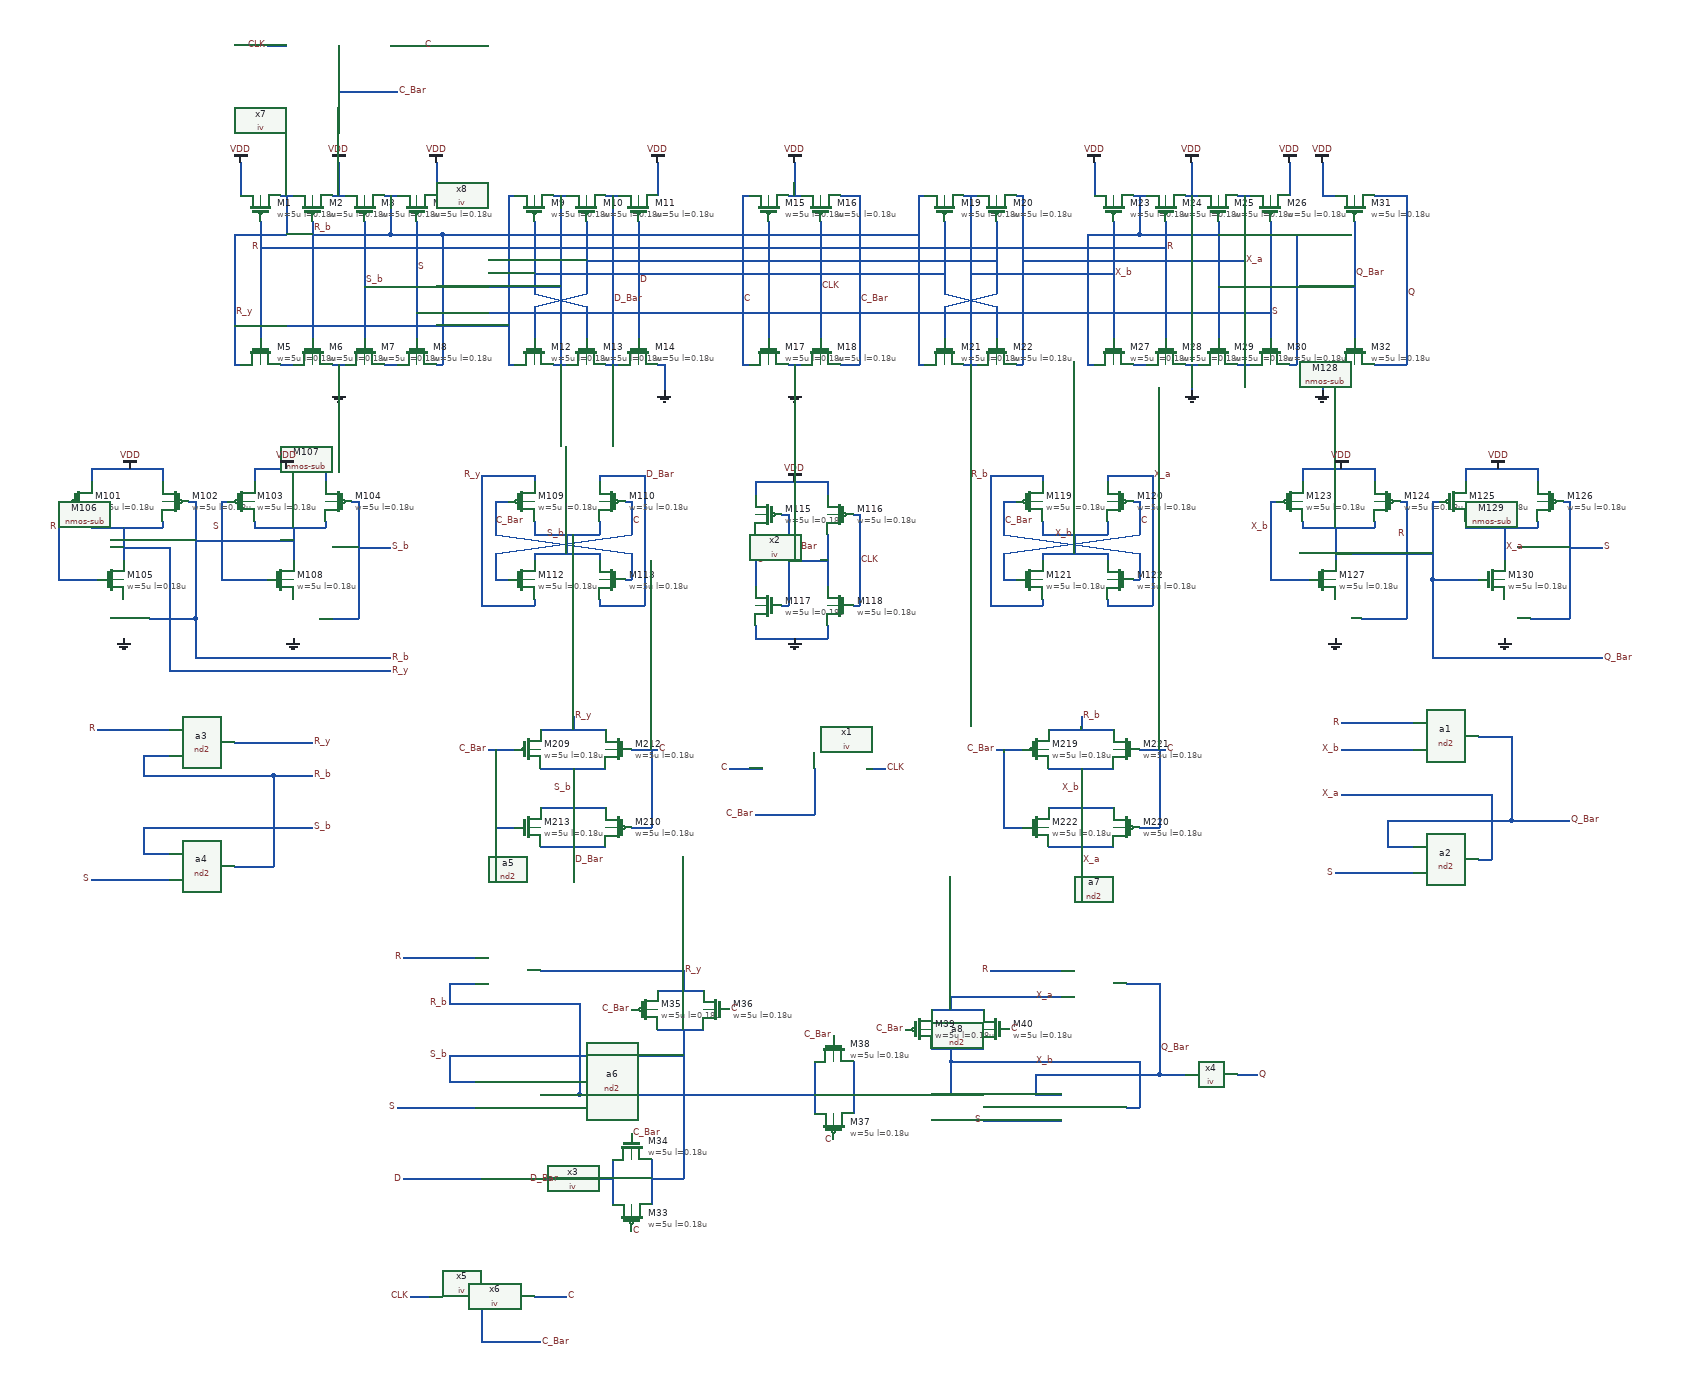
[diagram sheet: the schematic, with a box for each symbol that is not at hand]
v {xschem version=3.4.5 file_version=1.2
}
G {}
K {}
V {}
S {}
E {}
N 480 -1140 480 -1090 {
lab=VDD}
N 540 -1090 560 -1090 {
lab=R_y}
N 620 -1090 640 -1090 {
lab=VDD}
N 700 -1090 720 -1090 {
lab=R_b}
N 780 -1140 780 -1090 {
lab=VDD}
N 630 -1140 630 -1090 {
lab=VDD}
N 550 -1090 550 -1030 {
lab=R_y}
N 480 -1030 550 -1030 {
lab=R_y}
N 470 -1030 480 -1030 {
lab=R_y}
N 470 -830 480 -830 {
lab=R_y}
N 540 -830 560 -830 {
lab=#net1}
N 620 -830 640 -830 {
lab=GND}
N 700 -830 720 -830 {
lab=#net2}
N 780 -830 790 -830 {
lab=R_b}
N 710 -1090 710 -1030 {
lab=R_b}
N 590 -1030 710 -1030 {
lab=R_b}
N 630 -830 630 -790 {
lab=GND}
N 710 -1030 790 -1030 {
lab=R_b}
N 790 -1030 790 -850 {
lab=R_b}
N 890 -1090 900 -1090 {
lab=R_y}
N 890 -1090 890 -850 {
lab=R_y}
N 890 -830 900 -830 {
lab=R_y}
N 470 -890 890 -890 {
lab=R_y}
N 930 -920 1010 -940 {
lab=C}
N 930 -940 1010 -920 {
lab=C_Bar}
N 960 -1090 980 -1090 {
lab=S_b}
N 1040 -1090 1060 -1090 {
lab=D_Bar}
N 970 -1090 970 -850 {
lab=S_b}
N 960 -830 980 -830 {
lab=S_b}
N 1050 -1090 1050 -850 {
lab=D_Bar}
N 1040 -830 1060 -830 {
lab=D_Bar}
N 1090 -1050 1090 -880 {
lab=D}
N 1120 -1140 1120 -1090 {
lab=VDD}
N 1120 -830 1130 -830 {
lab=GND}
N 1130 -830 1130 -790 {
lab=GND}
N 1290 -1050 1290 -890 {
lab=C_Bar}
N 1370 -1050 1370 -890 {
lab=CLK}
N 1320 -1090 1340 -1090 {
lab=VDD}
N 1320 -830 1340 -830 {
lab=GND}
N 1330 -830 1330 -790 {
lab=GND}
N 1250 -1090 1260 -1090 {
lab=C}
N 1250 -1090 1250 -850 {
lab=C}
N 1250 -830 1260 -830 {
lab=C}
N 1330 -1140 1330 -1090 {
lab=VDD}
N 1290 -970 1410 -970 {
lab=C_Bar}
N 1010 -990 1250 -990 {
lab=C}
N 930 -970 1290 -970 {
lab=C_Bar}
N 670 -950 970 -950 {
lab=S_b}
N 1400 -1090 1430 -1090 {
lab=C_Bar}
N 1430 -1090 1430 -850 {
lab=C_Bar}
N 1400 -830 1430 -830 {
lab=C_Bar}
N 1410 -970 1430 -970 {
lab=C_Bar}
N 1520 -1090 1530 -1090 {
lab=R_b}
N 1520 -1090 1520 -850 {
lab=R_b}
N 1520 -830 1530 -830 {
lab=R_b}
N 1560 -920 1640 -940 {
lab=C}
N 1560 -940 1640 -920 {
lab=C_Bar}
N 1590 -1090 1610 -1090 {
lab=#net3}
N 1600 -1090 1600 -850 {
lab=#net3}
N 1590 -830 1610 -830 {
lab=#net3}
N 1680 -1090 1680 -850 {
lab=#net4}
N 1670 -1090 1680 -1090 {
lab=#net4}
N 1670 -830 1680 -830 {
lab=#net4}
N 1430 -970 1560 -970 {
lab=C_Bar}
N 1250 -990 1640 -990 {
lab=C}
N 1790 -1140 1790 -1090 {
lab=VDD}
N 1850 -1090 1870 -1090 {
lab=#net5}
N 1930 -1090 1950 -1090 {
lab=VDD}
N 2010 -1090 2030 -1090 {
lab=#net4}
N 2090 -1140 2090 -1090 {
lab=VDD}
N 1940 -1140 1940 -1090 {
lab=VDD}
N 1780 -830 1790 -830 {
lab=#net5}
N 1820 -1050 1820 -890 {
lab=#net3}
N 1900 -1050 1900 -890 {
lab=R}
N 1980 -1050 1980 -890 {
lab=#net5}
N 2060 -1050 2060 -890 {
lab=S}
N 1850 -830 1870 -830 {
lab=#net6}
N 1930 -830 1950 -830 {
lab=GND}
N 2010 -830 2030 -830 {
lab=#net7}
N 2090 -830 2100 -830 {
lab=#net4}
N 1940 -830 1940 -790 {
lab=GND}
N 1600 -970 1820 -970 {
lab=#net3}
N 930 -1050 930 -940 {
lab=C_Bar}
N 1010 -1050 1010 -940 {
lab=C}
N 930 -920 930 -890 {
lab=C}
N 1010 -920 1010 -890 {
lab=C_Bar}
N 1560 -920 1560 -890 {
lab=C}
N 1640 -920 1640 -890 {
lab=C_Bar}
N 1560 -1050 1560 -940 {
lab=C_Bar}
N 1640 -1050 1640 -940 {
lab=C}
N 750 -910 2060 -910 {
lab=S}
N 2140 -1090 2160 -1090 {
lab=VDD}
N 2140 -1140 2140 -1090 {
lab=VDD}
N 2190 -1050 2190 -890 {
lab=#net5}
N 2140 -830 2160 -830 {
lab=GND}
N 2140 -830 2140 -790 {
lab=GND}
N 510 -1010 1900 -1010 {
lab=R}
N 790 -1030 1520 -1030 {
lab=R_b}
N 790 -850 790 -830 {
lab=R_b}
N 510 -1050 510 -870 {
lab=R}
N 590 -1050 590 -870 {
lab=R_b}
N 670 -1050 670 -870 {
lab=S_b}
N 750 -1050 750 -870 {
lab=S}
N 470 -1030 470 -830 {
lab=R_y}
N 1680 -990 2020 -990 {
lab=#net4}
N 1780 -950 1780 -850 {
lab=#net5}
N 1980 -950 2190 -950 {
lab=#net5}
N 890 -850 890 -830 {
lab=R_y}
N 930 -890 930 -870 {
lab=C}
N 1010 -890 1010 -870 {
lab=C_Bar}
N 1050 -850 1050 -830 {
lab=D_Bar}
N 1090 -880 1090 -870 {
lab=D}
N 1250 -850 1250 -830 {
lab=C}
N 1290 -890 1290 -870 {
lab=C_Bar}
N 1370 -890 1370 -870 {
lab=CLK}
N 1430 -850 1430 -830 {
lab=C_Bar}
N 1520 -850 1520 -830 {
lab=R_b}
N 1560 -890 1560 -870 {
lab=C}
N 1600 -850 1600 -830 {
lab=#net3}
N 1640 -890 1640 -870 {
lab=C_Bar}
N 1680 -850 1680 -830 {
lab=#net4}
N 1780 -850 1780 -830 {
lab=#net5}
N 1820 -890 1820 -870 {
lab=#net3}
N 1900 -890 1900 -870 {
lab=R}
N 1980 -890 1980 -870 {
lab=#net5}
N 2060 -890 2060 -870 {
lab=S}
N 2190 -890 2190 -870 {
lab=#net5}
N 250 -590 250 -580 {
lab=R_y}
N 250 -580 360 -580 {
lab=R_y}
N 360 -590 360 -580 {
lab=R_y}
N 300 -580 300 -530 {
lab=R_y}
N 200 -620 210 -620 {
lab=R}
N 200 -620 200 -500 {
lab=R}
N 200 -500 260 -500 {
lab=R}
N 400 -620 410 -620 {
lab=R_b}
N 410 -620 410 -440 {
lab=R_b}
N 340 -440 410 -440 {
lab=R_b}
N 250 -670 250 -650 {
lab=VDD}
N 250 -670 360 -670 {
lab=VDD}
N 360 -670 360 -650 {
lab=VDD}
N 610 -590 610 -580 {
lab=R_b}
N 500 -580 610 -580 {
lab=R_b}
N 500 -590 500 -580 {
lab=R_b}
N 560 -580 560 -530 {
lab=R_b}
N 650 -620 660 -620 {
lab=S_b}
N 450 -620 460 -620 {
lab=S}
N 610 -670 610 -650 {
lab=VDD}
N 500 -670 610 -670 {
lab=VDD}
N 500 -670 500 -650 {
lab=VDD}
N 410 -560 560 -560 {
lab=R_b}
N 300 -550 370 -550 {
lab=R_y}
N 370 -550 370 -360 {
lab=R_y}
N 450 -500 520 -500 {
lab=S}
N 450 -620 450 -500 {
lab=S}
N 660 -620 660 -440 {
lab=S_b}
N 600 -440 660 -440 {
lab=S_b}
N 1780 -1030 1860 -1030 {
lab=#net5}
N 1780 -1030 1780 -950 {
lab=#net5}
N 2020 -1030 2100 -1030 {
lab=#net4}
N 2100 -1030 2100 -830 {
lab=#net4}
N 1860 -1030 1980 -1030 {
lab=#net5}
N 1860 -1090 1860 -1030 {
lab=#net5}
N 330 -120 330 -80 {
lab=S_b}
N 330 -80 370 -80 {
lab=S_b}
N 330 -230 370 -230 {
lab=R_b}
N 470 -60 530 -60 {
lab=R_b}
N 260 -270 370 -270 {
lab=R}
N 250 -40 370 -40 {
lab=S}
N 330 -120 590 -120 {
lab=S_b}
N 470 -250 590 -250 {
lab=R_y}
N 370 -360 710 -360 {
lab=R_y}
N 660 -550 710 -550 {
lab=S_b}
N 410 -440 410 -380 {
lab=R_b}
N 410 -380 710 -380 {
lab=R_b}
N 530 -200 590 -200 {
lab=R_b}
N 330 -200 530 -200 {
lab=R_b}
N 530 -200 530 -60 {
lab=R_b}
N 330 -230 330 -200 {
lab=R_b}
N 930 -590 930 -570 {
lab=#net8}
N 930 -570 1030 -570 {
lab=#net8}
N 1030 -590 1030 -570 {
lab=#net8}
N 930 -540 930 -530 {
lab=#net8}
N 930 -540 1030 -540 {
lab=#net8}
N 1030 -540 1030 -530 {
lab=#net8}
N 980 -570 980 -540 {
lab=#net8}
N 930 -470 930 -460 {
lab=R_y}
N 1030 -470 1030 -460 {
lab=D_Bar}
N 930 -660 930 -650 {
lab=R_y}
N 1030 -660 1030 -650 {
lab=D_Bar}
N 1070 -620 1080 -620 {
lab=C}
N 1080 -620 1080 -570 {
lab=C}
N 870 -540 1080 -570 {
lab=C}
N 870 -540 870 -500 {
lab=C}
N 870 -500 890 -500 {
lab=C}
N 870 -620 890 -620 {
lab=C_Bar}
N 870 -620 870 -570 {
lab=C_Bar}
N 870 -570 1080 -540 {
lab=C_Bar}
N 1080 -540 1080 -500 {
lab=C_Bar}
N 1070 -500 1080 -500 {
lab=C_Bar}
N 850 -660 930 -660 {
lab=R_y}
N 1030 -660 1100 -660 {
lab=D_Bar}
N 1100 -660 1100 -460 {
lab=D_Bar}
N 1030 -460 1100 -460 {
lab=D_Bar}
N 850 -460 930 -460 {
lab=R_y}
N 850 -660 850 -460 {
lab=R_y}
N 940 -90 1040 -90 {
lab=D_Bar}
N 940 -150 1040 -150 {
lab=S_b}
N 940 -210 1040 -210 {
lab=S_b}
N 940 -270 1040 -270 {
lab=R_y}
N 990 -210 990 -150 {
lab=S_b}
N 860 -240 900 -240 {
lab=C_Bar}
N 990 -90 990 -70 {
lab=D_Bar}
N 990 -290 990 -270 {
lab=R_y}
N 970 -850 970 -830 {
lab=S_b}
N 870 -120 900 -120 {
lab=C_Bar}
N 870 -240 870 -120 {
lab=C_Bar}
N 1080 -240 1120 -240 {
lab=C}
N 1110 -240 1110 -120 {
lab=C}
N 1080 -120 1110 -120 {
lab=C}
N 1270 -430 1270 -410 {
lab=GND}
N 1270 -410 1380 -410 {
lab=GND}
N 1380 -430 1380 -410 {
lab=GND}
N 1270 -650 1270 -630 {
lab=VDD}
N 1270 -650 1380 -650 {
lab=VDD}
N 1380 -650 1380 -630 {
lab=VDD}
N 1420 -600 1430 -600 {
lab=CLK}
N 1430 -600 1430 -460 {
lab=CLK}
N 1420 -460 1430 -460 {
lab=CLK}
N 1310 -600 1320 -600 {
lab=C_Bar}
N 1320 -600 1320 -460 {
lab=C_Bar}
N 1310 -460 1320 -460 {
lab=C_Bar}
N 1270 -570 1270 -490 {
lab=C}
N 1380 -570 1380 -490 {
lab=C_Bar}
N 1320 -530 1380 -530 {
lab=C_Bar}
N 1360 -210 1360 -140 {
lab=C_Bar}
N 1230 -210 1280 -210 {
lab=C}
N 1440 -210 1470 -210 {
lab=#net9}
N 1270 -140 1360 -140 {
lab=C_Bar}
N 1710 -590 1710 -570 {
lab=#net8}
N 1710 -570 1810 -570 {
lab=#net8}
N 1810 -590 1810 -570 {
lab=#net8}
N 1710 -540 1710 -530 {
lab=#net8}
N 1710 -540 1810 -540 {
lab=#net8}
N 1810 -540 1810 -530 {
lab=#net8}
N 1760 -570 1760 -540 {
lab=#net8}
N 1710 -470 1710 -460 {
lab=R_y}
N 1810 -470 1810 -460 {
lab=D_Bar}
N 1710 -660 1710 -650 {
lab=R_y}
N 1810 -660 1810 -650 {
lab=D_Bar}
N 1850 -620 1860 -620 {
lab=C}
N 1860 -620 1860 -570 {
lab=C}
N 1650 -540 1860 -570 {
lab=C}
N 1650 -540 1650 -500 {
lab=C}
N 1650 -500 1670 -500 {
lab=C}
N 1650 -620 1670 -620 {
lab=C_Bar}
N 1650 -620 1650 -570 {
lab=C_Bar}
N 1650 -570 1860 -540 {
lab=C_Bar}
N 1860 -540 1860 -500 {
lab=C_Bar}
N 1850 -500 1860 -500 {
lab=C_Bar}
N 1630 -660 1710 -660 {
lab=R_y}
N 1810 -660 1880 -660 {
lab=D_Bar}
N 1880 -660 1880 -460 {
lab=D_Bar}
N 1810 -460 1880 -460 {
lab=D_Bar}
N 1630 -460 1710 -460 {
lab=R_y}
N 1630 -660 1630 -460 {
lab=R_y}
N 1720 -90 1820 -90 {
lab=D_Bar}
N 1720 -150 1820 -150 {
lab=S_b}
N 1720 -210 1820 -210 {
lab=S_b}
N 1720 -270 1820 -270 {
lab=R_y}
N 1770 -210 1770 -150 {
lab=S_b}
N 1640 -240 1680 -240 {
lab=C_Bar}
N 1770 -90 1770 -70 {
lab=D_Bar}
N 1770 -290 1770 -270 {
lab=R_y}
N 1650 -120 1680 -120 {
lab=C_Bar}
N 1650 -240 1650 -120 {
lab=C_Bar}
N 1860 -240 1900 -240 {
lab=C}
N 1890 -240 1890 -120 {
lab=C}
N 1860 -120 1890 -120 {
lab=C}
N 2110 -590 2110 -580 {
lab=R_y}
N 2110 -580 2220 -580 {
lab=R_y}
N 2220 -590 2220 -580 {
lab=R_y}
N 2160 -580 2160 -530 {
lab=R_y}
N 2060 -620 2070 -620 {
lab=R}
N 2060 -620 2060 -500 {
lab=R}
N 2060 -500 2120 -500 {
lab=R}
N 2260 -620 2270 -620 {
lab=R_b}
N 2270 -620 2270 -440 {
lab=R_b}
N 2200 -440 2270 -440 {
lab=R_b}
N 2110 -670 2110 -650 {
lab=VDD}
N 2110 -670 2220 -670 {
lab=VDD}
N 2220 -670 2220 -650 {
lab=VDD}
N 2470 -590 2470 -580 {
lab=R_b}
N 2360 -580 2470 -580 {
lab=R_b}
N 2360 -590 2360 -580 {
lab=R_b}
N 2420 -580 2420 -530 {
lab=R_b}
N 2510 -620 2520 -620 {
lab=S_b}
N 2310 -620 2320 -620 {
lab=S}
N 2470 -670 2470 -650 {
lab=VDD}
N 2360 -670 2470 -670 {
lab=VDD}
N 2360 -670 2360 -650 {
lab=VDD}
N 2310 -500 2380 -500 {
lab=S}
N 2310 -620 2310 -500 {
lab=S}
N 2520 -620 2520 -440 {
lab=S_b}
N 2460 -440 2520 -440 {
lab=S_b}
N 2240 -130 2240 -90 {
lab=S_b}
N 2240 -90 2280 -90 {
lab=S_b}
N 2170 -280 2280 -280 {
lab=R}
N 2160 -50 2280 -50 {
lab=S}
N 2520 -550 2570 -550 {
lab=S_b}
N 2220 -1090 2270 -1090 {}
N 2270 -1090 2270 -830 {}
N 2220 -830 2270 -830 {}
N 2020 -1090 2020 -990 {}
N 2160 -540 2310 -540 {}
N 2310 -500 2310 -380 {}
N 2310 -380 2570 -380 {}
N 2430 -260 2430 -130 {}
N 2170 -240 2280 -240 {}
N 2380 -70 2400 -70 {}
N 2400 -170 2400 -70 {}
N 2170 -170 2400 -170 {}
N 2380 -260 2430 -260 {}
N 2240 -130 2430 -130 {}
N 2430 -130 2520 -130 {}
N 800 230 800 270 {
lab=S_b}
N 800 270 840 270 {
lab=S_b}
N 800 120 840 120 {
lab=R_b}
N 940 290 1000 290 {
lab=R_b}
N 730 80 840 80 {
lab=R}
N 720 310 840 310 {
lab=S}
N 940 100 1060 100 {
lab=R_y}
N 800 150 1000 150 {
lab=R_b}
N 1000 150 1000 290 {
lab=R_b}
N 800 120 800 150 {
lab=R_b}
N 730 420 850 420 {}
N 1030 420 1050 420 {
lab=D_Bar}
N 930 420 1030 420 {}
N 1110 420 1160 420 {}
N 1160 190 1160 420 {}
N 1060 100 1160 100 {}
N 1160 100 1160 130 {}
N 800 230 1160 230 {}
N 1700 290 1740 290 {
lab=S_b}
N 1630 100 1740 100 {
lab=R}
N 1620 330 1740 330 {
lab=S}
N 1630 140 1740 140 {}
N 1840 310 1860 310 {}
N 1840 120 1890 120 {}
N 1700 260 1890 260 {}
N 1570 140 1570 160 {}
N 1570 140 1630 140 {}
N 1570 220 1570 240 {}
N 1570 240 1860 240 {}
N 1860 240 1860 310 {}
N 1700 260 1700 290 {}
N 1890 120 1890 260 {}
N 1570 240 1570 290 {}
N 1890 260 1930 260 {}
N 2010 260 2040 260 {}
N 1000 290 1360 290 {}
N 1420 290 1570 290 {}
N 850 600 850 670 {
lab=C_Bar}
N 930 600 980 600 {
lab=C}
N 740 600 770 600 {
lab=#net9}
N 850 670 940 670 {
lab=C_Bar}
N 1120 130 1190 130 {}
N 1120 190 1190 190 {}
N 1050 390 1050 460 {}
N 1110 390 1110 460 {}
N 1360 240 1360 320 {}
N 1420 240 1420 320 {}
N 1540 160 1620 160 {}
N 1540 220 1620 220 {}
N 630 -1320 630 -1250 {
lab=C_Bar}
N 710 -1320 760 -1320 {
lab=C}
N 520 -1320 550 -1320 {
lab=#net9}
N 630 -1250 720 -1250 {
lab=C_Bar}
C {pmos-sub.sym} 510 -1070 3 0 {name=M1 model=pfet substrate=VDD w=5u l=0.18u m=1}
C {pmos-sub.sym} 590 -1070 3 0 {name=M2 model=pfet substrate=VDD w=5u l=0.18u m=1}
C {pmos-sub.sym} 670 -1070 3 0 {name=M3 model=pfet substrate=VDD w=5u l=0.18u m=1}
C {pmos-sub.sym} 750 -1070 3 0 {name=M4 model=pfet substrate=VDD w=5u l=0.18u m=1}
C {vdd.sym} 480 -1140 0 0 {name=l1 lab=VDD}
C {vdd.sym} 630 -1140 0 0 {name=l2 lab=VDD}
C {vdd.sym} 780 -1140 0 0 {name=l3 lab=VDD}
C {nmos-sub.sym} 510 -850 1 0 {name=M5 model=nfet substrate=GND w=5u l=0.18u m=1}
C {nmos-sub.sym} 590 -850 1 0 {name=M6 model=nfet substrate=GND w=5u l=0.18u m=1}
C {nmos-sub.sym} 670 -850 1 0 {name=M7 model=nfet substrate=GND w=5u l=0.18u m=1}
C {nmos-sub.sym} 750 -850 1 0 {name=M8 model=nfet substrate=GND w=5u l=0.18u m=1}
C {gnd.sym} 630 -790 0 0 {name=l4 lab=GND}
C {lab_pin.sym} 510 -1010 0 0 {name=p2 sig_type=std_logic lab=R}
C {lab_pin.sym} 750 -980 0 1 {name=p4 sig_type=std_logic lab=S}
C {pmos-sub.sym} 930 -1070 3 0 {name=M9 model=pfet substrate=VDD w=5u l=0.18u m=1}
C {pmos-sub.sym} 1010 -1070 3 0 {name=M10 model=pfet substrate=VDD w=5u l=0.18u m=1}
C {pmos-sub.sym} 1090 -1070 3 0 {name=M11 model=pfet substrate=VDD w=5u l=0.18u m=1}
C {nmos-sub.sym} 930 -850 1 0 {name=M12 model=nfet substrate=GND w=5u l=0.18u m=1}
C {nmos-sub.sym} 1010 -850 1 0 {name=M13 model=nfet substrate=GND w=5u l=0.18u m=1}
C {nmos-sub.sym} 1090 -850 1 0 {name=M14 model=nfet substrate=GND w=5u l=0.18u m=1}
C {vdd.sym} 1120 -1140 0 0 {name=l9 lab=VDD}
C {gnd.sym} 1130 -790 0 0 {name=l10 lab=GND}
C {lab_pin.sym} 1090 -960 0 1 {name=p5 sig_type=std_logic lab=D}
C {lab_pin.sym} 1050 -930 0 1 {name=p14 sig_type=std_logic lab=D_Bar}
C {pmos-sub.sym} 1290 -1070 3 0 {name=M15 model=pfet substrate=VDD w=5u l=0.18u m=1}
C {pmos-sub.sym} 1370 -1070 3 0 {name=M16 model=pfet substrate=VDD w=5u l=0.18u m=1}
C {nmos-sub.sym} 1290 -850 1 0 {name=M17 model=nfet substrate=GND w=5u l=0.18u m=1}
C {nmos-sub.sym} 1370 -850 1 0 {name=M18 model=nfet substrate=GND w=5u l=0.18u m=1}
C {gnd.sym} 1330 -790 0 0 {name=l11 lab=GND}
C {vdd.sym} 1330 -1140 0 0 {name=l12 lab=VDD}
C {lab_pin.sym} 1370 -950 2 0 {name=p17 sig_type=std_logic lab=CLK}
C {lab_pin.sym} 1430 -930 2 0 {name=p18 sig_type=std_logic lab=C_Bar}
C {lab_pin.sym} 1250 -930 2 0 {name=p19 sig_type=std_logic lab=C}
C {pmos-sub.sym} 1560 -1070 3 0 {name=M19 model=pfet substrate=VDD w=5u l=0.18u m=1}
C {pmos-sub.sym} 1640 -1070 3 0 {name=M20 model=pfet substrate=VDD w=5u l=0.18u m=1}
C {nmos-sub.sym} 1560 -850 1 0 {name=M21 model=nfet substrate=GND w=5u l=0.18u m=1}
C {nmos-sub.sym} 1640 -850 1 0 {name=M22 model=nfet substrate=GND w=5u l=0.18u m=1}
C {pmos-sub.sym} 1820 -1070 3 0 {name=M23 model=pfet substrate=VDD w=5u l=0.18u m=1}
C {pmos-sub.sym} 1900 -1070 3 0 {name=M24 model=pfet substrate=VDD w=5u l=0.18u m=1}
C {pmos-sub.sym} 1980 -1070 3 0 {name=M25 model=pfet substrate=VDD w=5u l=0.18u m=1}
C {pmos-sub.sym} 2060 -1070 3 0 {name=M26 model=pfet substrate=VDD w=5u l=0.18u m=1}
C {vdd.sym} 1790 -1140 0 0 {name=l13 lab=VDD}
C {vdd.sym} 1940 -1140 0 0 {name=l14 lab=VDD}
C {vdd.sym} 2090 -1140 0 0 {name=l15 lab=VDD}
C {nmos-sub.sym} 1820 -850 1 0 {name=M27 model=nfet substrate=GND w=5u l=0.18u m=1}
C {nmos-sub.sym} 1900 -850 1 0 {name=M28 model=nfet substrate=GND w=5u l=0.18u m=1}
C {nmos-sub.sym} 1980 -850 1 0 {name=M29 model=nfet substrate=GND w=5u l=0.18u m=1}
C {nmos-sub.sym} 2060 -850 1 0 {name=M30 model=nfet substrate=GND w=5u l=0.18u m=1}
C {gnd.sym} 1940 -790 0 0 {name=l16 lab=GND}
C {pmos-sub.sym} 2190 -1070 3 0 {name=M31 model=pfet substrate=VDD w=5u l=0.18u m=1}
C {nmos-sub.sym} 2190 -850 1 0 {name=M32 model=nfet substrate=GND w=5u l=0.18u m=1}
C {vdd.sym} 2140 -1140 0 0 {name=l21 lab=VDD}
C {gnd.sym} 2140 -790 0 0 {name=l22 lab=GND}
C {lab_pin.sym} 2270 -940 2 0 {name=p24 sig_type=std_logic lab=Q}
C {pmos-sub.sym} 230 -620 0 0 {name=M101 model=pfet substrate=VDD w=5u l=0.18u m=1}
C {nmos-sub.sym} 280 -500 0 0 {name=M105 model=nfet substrate=GND w=5u l=0.18u m=1}
C {pmos-sub.sym} 380 -620 0 1 {name=M102 model=pfet substrate=VDD w=5u l=0.18u m=1}
C {nmos-sub.sym} 320 -440 0 1 {name=M106 model=nfet substrate=GND w=5u l=0.18u m=1}
C {gnd.sym} 300 -410 0 0 {name=l5 lab=GND}
C {vdd.sym} 310 -670 0 0 {name=l6 lab=VDD}
C {lab_pin.sym} 200 -580 0 0 {name=p1 sig_type=std_logic lab=R}
C {pmos-sub.sym} 630 -620 0 1 {name=M104 model=pfet substrate=VDD w=5u l=0.18u m=1}
C {nmos-sub.sym} 540 -500 0 0 {name=M108 model=nfet substrate=GND w=5u l=0.18u m=1}
C {pmos-sub.sym} 480 -620 0 0 {name=M103 model=pfet substrate=VDD w=5u l=0.18u m=1}
C {nmos-sub.sym} 580 -440 0 1 {name=M107 model=nfet substrate=GND w=5u l=0.18u m=1}
C {gnd.sym} 560 -410 0 1 {name=l7 lab=GND}
C {vdd.sym} 550 -670 0 1 {name=l8 lab=VDD}
C {lab_pin.sym} 450 -580 0 0 {name=p3 sig_type=std_logic lab=S}
C {nd2.sym} 410 -250 0 0 {name=a3 del=120}
C {nd2.sym} 410 -60 0 0 {name=a4 del=120}
C {lab_pin.sym} 260 -270 0 0 {name=p32 sig_type=std_logic lab=R}
C {lab_pin.sym} 250 -40 0 0 {name=p33 sig_type=std_logic lab=S}
C {lab_pin.sym} 710 -360 0 1 {name=p6 sig_type=std_logic lab=R_y}
C {lab_pin.sym} 590 -250 0 1 {name=p7 sig_type=std_logic lab=R_y}
C {lab_pin.sym} 590 -120 0 1 {name=p8 sig_type=std_logic lab=S_b}
C {lab_pin.sym} 710 -550 0 1 {name=p9 sig_type=std_logic lab=S_b}
C {lab_pin.sym} 710 -380 0 1 {name=p10 sig_type=std_logic lab=R_b}
C {lab_pin.sym} 590 -200 0 1 {name=p11 sig_type=std_logic lab=R_b}
C {lab_pin.sym} 590 -1040 0 1 {name=p12 sig_type=std_logic lab=R_b}
C {lab_pin.sym} 670 -960 0 1 {name=p13 sig_type=std_logic lab=S_b}
C {lab_pin.sym} 470 -910 0 1 {name=p15 sig_type=std_logic lab=R_y}
C {pmos-sub.sym} 910 -620 0 0 {name=M109 model=pfet substrate=VDD w=5u l=0.18u m=1}
C {pmos-sub.sym} 1050 -620 0 1 {name=M110 model=pfet substrate=VDD w=5u l=0.18u m=1}
C {nmos-sub.sym} 910 -500 2 1 {name=M112 model=nfet substrate=GND w=5u l=0.18u m=1}
C {nmos-sub.sym} 1050 -500 2 0 {name=M113 model=nfet substrate=GND w=5u l=0.18u m=1}
C {lab_pin.sym} 870 -590 0 1 {name=p16 sig_type=std_logic lab=C_Bar}
C {lab_pin.sym} 1080 -590 0 1 {name=p20 sig_type=std_logic lab=C}
C {lab_pin.sym} 1100 -660 0 1 {name=p21 sig_type=std_logic lab=D_Bar}
C {pmos-sub.sym} 1060 -120 2 0 {name=M210 model=pfet substrate=VDD w=5u l=0.18u m=1}
C {nmos-sub.sym} 1060 -240 0 1 {name=M212 model=nfet substrate=GND w=5u l=0.18u m=1}
C {pmos-sub.sym} 920 -240 2 1 {name=M209 model=pfet substrate=VDD w=5u l=0.18u m=1}
C {nmos-sub.sym} 920 -120 0 0 {name=M213 model=nfet substrate=GND w=5u l=0.18u m=1}
C {lab_pin.sym} 1120 -240 2 0 {name=p23 sig_type=std_logic lab=C}
C {lab_pin.sym} 860 -240 2 1 {name=p26 sig_type=std_logic lab=C_Bar}
C {lab_pin.sym} 990 -70 2 0 {name=p27 sig_type=std_logic lab=D_Bar}
C {lab_pin.sym} 990 -180 0 0 {name=p28 sig_type=std_logic lab=S_b}
C {lab_pin.sym} 990 -290 0 1 {name=p29 sig_type=std_logic lab=R_y}
C {lab_pin.sym} 850 -660 0 0 {name=p22 sig_type=std_logic lab=R_y}
C {pmos-sub.sym} 1290 -600 0 1 {name=M115 model=pfet substrate=VDD w=5u l=0.18u m=1}
C {pmos-sub.sym} 1400 -600 0 1 {name=M116 model=pfet substrate=VDD w=5u l=0.18u m=1}
C {nmos-sub.sym} 1290 -460 0 1 {name=M117 model=nfet substrate=GND w=5u l=0.18u m=1}
C {nmos-sub.sym} 1400 -460 2 0 {name=M118 model=nfet substrate=GND w=5u l=0.18u m=1}
C {gnd.sym} 1330 -410 0 0 {name=l17 lab=GND}
C {vdd.sym} 1330 -650 0 0 {name=l18 lab=VDD}
C {lab_pin.sym} 1430 -530 2 0 {name=p25 sig_type=std_logic lab=CLK}
C {lab_pin.sym} 1320 -550 2 0 {name=p30 sig_type=std_logic lab=C_Bar}
C {lab_pin.sym} 1270 -530 2 0 {name=p31 sig_type=std_logic lab=C}
C {iv.sym} 1400 -210 0 1 {name=x1 delay="70 ps" del=70}
C {iv.sym} 1320 -210 0 1 {name=x2 delay="70 ps" del=70}
C {lab_pin.sym} 1230 -210 2 1 {name=p34 sig_type=std_logic lab=C}
C {lab_pin.sym} 1270 -140 2 1 {name=p35 sig_type=std_logic lab=C_Bar}
C {lab_pin.sym} 1470 -210 2 0 {name=p36 sig_type=std_logic lab=CLK}
C {pmos-sub.sym} 1690 -620 0 0 {name=M119 model=pfet substrate=VDD w=5u l=0.18u m=1}
C {pmos-sub.sym} 1830 -620 0 1 {name=M120 model=pfet substrate=VDD w=5u l=0.18u m=1}
C {nmos-sub.sym} 1690 -500 2 1 {name=M121 model=nfet substrate=GND w=5u l=0.18u m=1}
C {nmos-sub.sym} 1830 -500 2 0 {name=M122 model=nfet substrate=GND w=5u l=0.18u m=1}
C {lab_pin.sym} 1650 -590 0 1 {name=p37 sig_type=std_logic lab=C_Bar}
C {lab_pin.sym} 1860 -590 0 1 {name=p38 sig_type=std_logic lab=C}
C {lab_pin.sym} 1880 -660 0 1 {name=p39 sig_type=std_logic lab=X_a}
C {pmos-sub.sym} 1840 -120 2 0 {name=M220 model=pfet substrate=VDD w=5u l=0.18u m=1}
C {nmos-sub.sym} 1840 -240 0 1 {name=M221 model=nfet substrate=GND w=5u l=0.18u m=1}
C {pmos-sub.sym} 1700 -240 2 1 {name=M219 model=pfet substrate=VDD w=5u l=0.18u m=1}
C {nmos-sub.sym} 1700 -120 0 0 {name=M222 model=nfet substrate=GND w=5u l=0.18u m=1}
C {lab_pin.sym} 1900 -240 2 0 {name=p40 sig_type=std_logic lab=C}
C {lab_pin.sym} 1640 -240 2 1 {name=p41 sig_type=std_logic lab=C_Bar}
C {lab_pin.sym} 1770 -70 2 0 {name=p42 sig_type=std_logic lab=X_a}
C {lab_pin.sym} 1770 -180 0 0 {name=p43 sig_type=std_logic lab=X_b}
C {lab_pin.sym} 1770 -290 0 1 {name=p44 sig_type=std_logic lab=R_b}
C {lab_pin.sym} 1630 -660 0 0 {name=p45 sig_type=std_logic lab=R_b}
C {pmos-sub.sym} 2090 -620 0 0 {name=M123 model=pfet substrate=VDD w=5u l=0.18u m=1}
C {nmos-sub.sym} 2140 -500 0 0 {name=M127 model=nfet substrate=GND w=5u l=0.18u m=1}
C {pmos-sub.sym} 2240 -620 0 1 {name=M124 model=pfet substrate=VDD w=5u l=0.18u m=1}
C {nmos-sub.sym} 2180 -440 0 1 {name=M128 model=nfet substrate=GND w=5u l=0.18u m=1}
C {gnd.sym} 2160 -410 0 0 {name=l19 lab=GND}
C {vdd.sym} 2170 -670 0 0 {name=l20 lab=VDD}
C {lab_pin.sym} 2060 -580 0 0 {name=p46 sig_type=std_logic lab=X_b}
C {pmos-sub.sym} 2490 -620 0 1 {name=M126 model=pfet substrate=VDD w=5u l=0.18u m=1}
C {nmos-sub.sym} 2400 -500 0 0 {name=M130 model=nfet substrate=GND w=5u l=0.18u m=1}
C {pmos-sub.sym} 2340 -620 0 0 {name=M125 model=pfet substrate=VDD w=5u l=0.18u m=1}
C {nmos-sub.sym} 2440 -440 0 1 {name=M129 model=nfet substrate=GND w=5u l=0.18u m=1}
C {gnd.sym} 2420 -410 0 1 {name=l23 lab=GND}
C {vdd.sym} 2410 -670 0 1 {name=l24 lab=VDD}
C {nd2.sym} 2320 -260 0 0 {name=a1 del=120}
C {nd2.sym} 2320 -70 0 0 {name=a2 del=120}
C {lab_pin.sym} 2170 -280 0 0 {name=p48 sig_type=std_logic lab=R}
C {lab_pin.sym} 2160 -50 0 0 {name=p49 sig_type=std_logic lab=S}
C {lab_pin.sym} 2570 -550 0 1 {name=p53 sig_type=std_logic lab=S}
C {lab_pin.sym} 2570 -380 0 1 {name=p54 sig_type=std_logic lab=Q_Bar}
C {lab_pin.sym} 2190 -970 2 0 {name=p56 sig_type=std_logic lab=Q_Bar}
C {lab_pin.sym} 2270 -570 0 0 {name=p57 sig_type=std_logic lab=R}
C {lab_pin.sym} 1900 -1010 0 1 {name=p58 sig_type=std_logic lab=R}
C {lab_pin.sym} 1820 -970 0 1 {name=p47 sig_type=std_logic lab=X_b}
C {lab_pin.sym} 2020 -990 0 1 {name=p59 sig_type=std_logic lab=X_a}
C {lab_pin.sym} 2420 -550 0 1 {name=p60 sig_type=std_logic lab=X_a}
C {lab_pin.sym} 2170 -170 0 0 {name=p55 sig_type=std_logic lab=X_a}
C {lab_pin.sym} 2170 -240 2 1 {name=p61 sig_type=std_logic lab=X_b}
C {lab_pin.sym} 2520 -130 0 1 {name=p50 sig_type=std_logic lab=Q_Bar}
C {nd2.sym} 880 100 0 0 {name=a5 del=120}
C {nd2.sym} 880 290 0 0 {name=a6 del=120}
C {lab_pin.sym} 730 80 0 0 {name=p51 sig_type=std_logic lab=R}
C {lab_pin.sym} 720 310 0 0 {name=p52 sig_type=std_logic lab=S}
C {lab_pin.sym} 1160 100 0 1 {name=p62 sig_type=std_logic lab=R_y}
C {lab_pin.sym} 800 230 0 0 {name=p63 sig_type=std_logic lab=S_b}
C {lab_pin.sym} 800 150 2 1 {name=p64 sig_type=std_logic lab=R_b}
C {iv.sym} 890 420 0 0 {name=x3 delay="70 ps" del=70}
C {lab_pin.sym} 730 420 0 0 {name=p65 sig_type=std_logic lab=D}
C {pmos-sub.sym} 1080 480 3 0 {name=M33 model=pfet substrate=VDD w=5u l=0.18u m=1}
C {nmos-sub.sym} 1080 370 1 0 {name=M34 model=nfet substrate=GND w=5u l=0.18u m=1}
C {lab_pin.sym} 970 420 3 0 {name=p66 sig_type=std_logic lab=D_Bar}
C {pmos-sub.sym} 1100 160 0 0 {name=M35 model=pfet substrate=VDD w=5u l=0.18u m=1}
C {nmos-sub.sym} 1210 160 2 0 {name=M36 model=nfet substrate=GND w=5u l=0.18u m=1}
C {lab_pin.sym} 1080 160 2 1 {name=p67 sig_type=std_logic lab=C_Bar}
C {lab_pin.sym} 1080 350 0 1 {name=p68 sig_type=std_logic lab=C_Bar}
C {lab_pin.sym} 1080 500 2 0 {name=p69 sig_type=std_logic lab=C}
C {lab_pin.sym} 1230 160 2 0 {name=p70 sig_type=std_logic lab=C}
C {pmos-sub.sym} 1390 340 3 0 {name=M37 model=pfet substrate=VDD w=5u l=0.18u m=1}
C {nmos-sub.sym} 1390 220 1 0 {name=M38 model=nfet substrate=GND w=5u l=0.18u m=1}
C {lab_pin.sym} 1390 200 2 1 {name=p71 sig_type=std_logic lab=C_Bar}
C {lab_pin.sym} 1390 360 0 0 {name=p72 sig_type=std_logic lab=C}
C {nd2.sym} 1780 120 0 0 {name=a7 del=120}
C {nd2.sym} 1780 310 0 0 {name=a8 del=120}
C {lab_pin.sym} 1630 100 0 0 {name=p73 sig_type=std_logic lab=R}
C {lab_pin.sym} 1620 330 0 0 {name=p74 sig_type=std_logic lab=S}
C {lab_pin.sym} 1730 240 1 0 {name=p75 sig_type=std_logic lab=X_b}
C {lab_pin.sym} 1730 140 1 1 {name=p76 sig_type=std_logic lab=X_a}
C {lab_pin.sym} 1890 220 0 1 {name=p77 sig_type=std_logic lab=Q_Bar}
C {pmos-sub.sym} 1520 190 0 0 {name=M39 model=pfet substrate=VDD w=5u l=0.18u m=1}
C {nmos-sub.sym} 1640 190 2 0 {name=M40 model=nfet substrate=GND w=5u l=0.18u m=1}
C {lab_pin.sym} 1500 190 2 1 {name=p78 sig_type=std_logic lab=C_Bar}
C {lab_pin.sym} 1660 190 2 0 {name=p79 sig_type=std_logic lab=C}
C {iv.sym} 1970 260 0 0 {name=x4 delay="70 ps" del=70}
C {lab_pin.sym} 2040 260 0 1 {name=p80 sig_type=std_logic lab=Q}
C {iv.sym} 810 600 0 0 {name=x5 delay="70 ps" del=70}
C {iv.sym} 890 600 0 0 {name=x6 delay="70 ps" del=70}
C {lab_pin.sym} 980 600 2 0 {name=p81 sig_type=std_logic lab=C}
C {lab_pin.sym} 940 670 2 0 {name=p82 sig_type=std_logic lab=C_Bar}
C {lab_pin.sym} 740 600 2 1 {name=p83 sig_type=std_logic lab=CLK}
C {lab_pin.sym} 2060 -910 0 1 {name=p84 sig_type=std_logic lab=S}
C {iv.sym} 590 -1320 0 0 {name=x7 delay="70 ps" del=70}
C {iv.sym} 670 -1320 0 0 {name=x8 delay="70 ps" del=70}
C {lab_pin.sym} 760 -1320 2 0 {name=p85 sig_type=std_logic lab=C}
C {lab_pin.sym} 720 -1250 2 0 {name=p86 sig_type=std_logic lab=C_Bar}
C {lab_pin.sym} 520 -1320 2 1 {name=p87 sig_type=std_logic lab=CLK}
C {lab_pin.sym} 980 -570 1 0 {name=p88 sig_type=std_logic lab=S_b}
C {lab_pin.sym} 1760 -570 1 0 {name=p89 sig_type=std_logic lab=X_b}
